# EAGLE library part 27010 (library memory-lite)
MEMORY

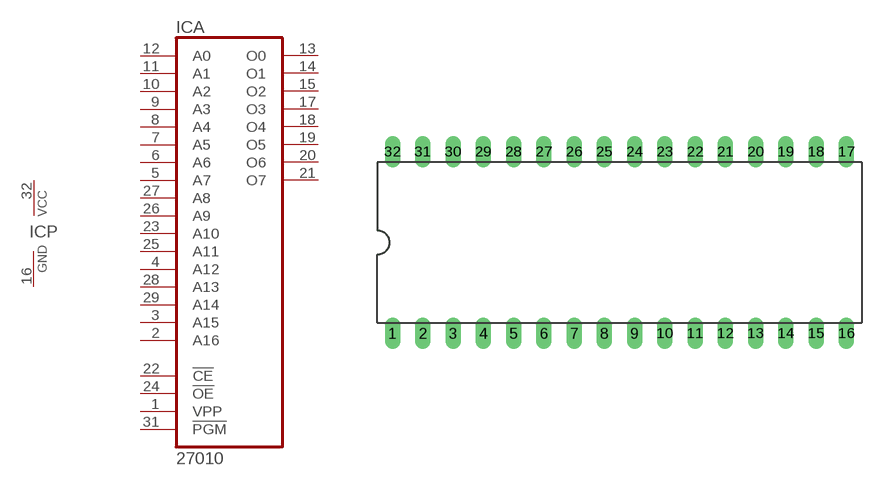
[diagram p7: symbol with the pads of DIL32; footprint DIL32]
Designator prefix IC; gates A=27010 P=PWRN

## 27010  [DIL32]
1  A:VPP  in
2  A:A16  in
3  A:A15  in
4  A:A12  in
5  A:A7  in
6  A:A6  in
7  A:A5  in
8  A:A4  in
9  A:A3  in
10  A:A2  in
11  A:A1  in
12  A:A0  in
13  A:O0  hiz
14  A:O1  hiz
15  A:O2  hiz
16  P:GND  pwr
17  A:O3  hiz
18  A:O4  hiz
19  A:O5  hiz
20  A:O6  hiz
21  A:O7  hiz
22  A:!CE  in
23  A:A10  in
24  A:!OE  in
25  A:A11  in
26  A:A9  in
27  A:A8  in
28  A:A13  in
29  A:A14  in
31  A:!PGM  in
32  P:VCC  pwr

## Footprint DIL32 (pad centres in mm)
Dual In Line Package
drill 0.813 long: 1 -19.05,-7.62; 2 -16.51,-7.62; 3 -13.97,-7.62; 4 -11.43,-7.62; 5 -8.89,-7.62; 6 -6.35,-7.62; 7 -3.81,-7.62; 8 -1.27,-7.62; 9 1.27,-7.62; 10 3.81,-7.62; 11 6.35,-7.62; 12 8.89,-7.62; 13 11.43,-7.62; 14 13.97,-7.62; 15 16.51,-7.62; 16 19.05,-7.62; 17 19.05,7.62; 18 16.51,7.62; 19 13.97,7.62; 20 11.43,7.62; 21 8.89,7.62; 22 6.35,7.62; 23 3.81,7.62; 24 1.27,7.62; 25 -1.27,7.62; 26 -3.81,7.62; 27 -6.35,7.62; 28 -8.89,7.62; 29 -11.43,7.62; 30 -13.97,7.62; 31 -16.51,7.62; 32 -19.05,7.62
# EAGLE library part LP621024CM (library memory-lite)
MEMORY

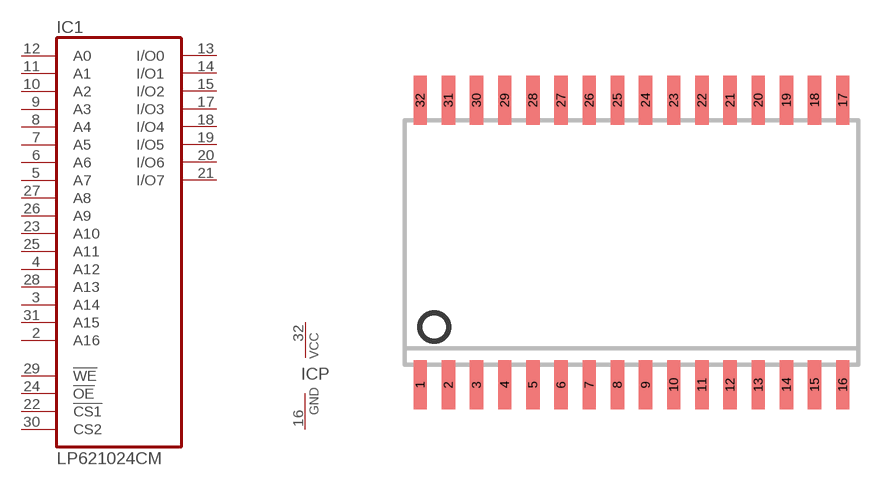
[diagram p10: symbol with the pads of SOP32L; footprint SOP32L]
Designator prefix IC; gates 1=621024 P=PWRN

## LP621024CM  [SOP32L]
1  1:NC  nc
2  1:A16  in
3  1:A14  in
4  1:A12  in
5  1:A7  in
6  1:A6  in
7  1:A5  in
8  1:A4  in
9  1:A3  in
10  1:A2  in
11  1:A1  in
12  1:A0  in
13  1:I/O0
14  1:I/O1
15  1:I/O2
16  P:GND  pwr
17  1:I/O3
18  1:I/O4
19  1:I/O5
20  1:I/O6
21  1:I/O7
22  1:!CS1  in
23  1:A10  in
24  1:!OE  in
25  1:A11  in
26  1:A9  in
27  1:A8  in
28  1:A13  in
29  1:!WE  in
30  1:CS2  in
31  1:A15  in
32  P:VCC  pwr

## Footprint SOP32L (pad centres in mm)
Small Outline Package large
smd 0.6 x 2.2: 1 -9.525,-6.416; 2 -8.255,-6.416; 3 -6.985,-6.416; 4 -5.715,-6.416; 5 -4.445,-6.416; 6 -3.175,-6.416; 7 -1.905,-6.416; 8 -0.635,-6.416; 9 0.635,-6.416; 10 1.905,-6.416; 11 3.175,-6.416; 12 4.445,-6.416; 13 5.715,-6.416; 14 6.985,-6.416; 15 8.255,-6.416; 16 9.525,-6.416; 17 9.525,6.416; 18 8.255,6.416; 19 6.985,6.416; 20 5.715,6.416; 21 4.445,6.416; 22 3.175,6.416; 23 1.905,6.416; 24 0.635,6.416; 25 -0.635,6.416; 26 -1.905,6.416; 27 -3.175,6.416; 28 -4.445,6.416; 29 -5.715,6.416; 30 -6.985,6.416; 31 -8.255,6.416; 32 -9.525,6.416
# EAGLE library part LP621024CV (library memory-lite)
MEMORY

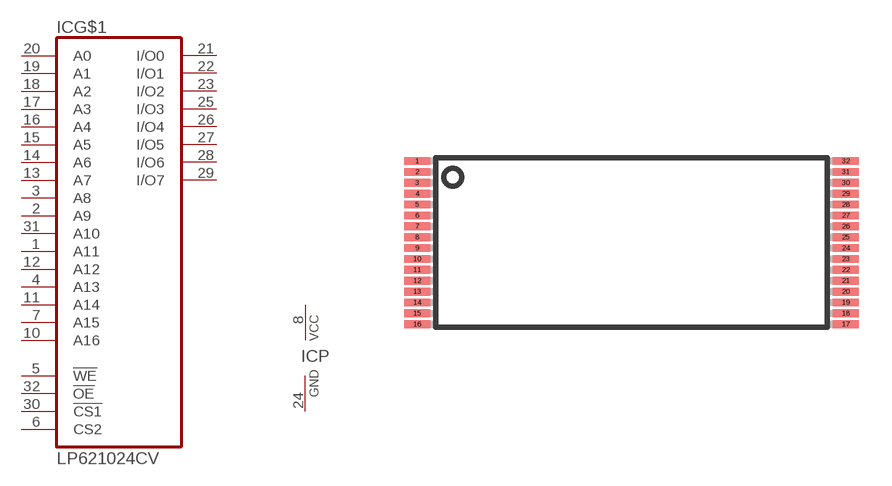
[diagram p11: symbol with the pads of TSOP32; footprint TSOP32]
Designator prefix IC; gates G$1=621024 P=PWRN

## LP621024CV  [TSOP32]
1  G$1:A11  in
2  G$1:A9  in
3  G$1:A8  in
4  G$1:A13  in
5  G$1:!WE  in
6  G$1:CS2  in
7  G$1:A15  in
8  P:VCC  pwr
9  G$1:NC  nc
10  G$1:A16  in
11  G$1:A14  in
12  G$1:A12  in
13  G$1:A7  in
14  G$1:A6  in
15  G$1:A5  in
16  G$1:A4  in
17  G$1:A3  in
18  G$1:A2  in
19  G$1:A1  in
20  G$1:A0  in
21  G$1:I/O0
22  G$1:I/O1
23  G$1:I/O2
24  P:GND  pwr
25  G$1:I/O3
26  G$1:I/O4
27  G$1:I/O5
28  G$1:I/O6
29  G$1:I/O7
30  G$1:!CS1  in
31  G$1:A10  in
32  G$1:!OE  in

## Footprint TSOP32 (pad centres in mm)
Thin Small Outline Package
smd 1.2 x 0.36: 1 -9.85,3.75; 2 -9.85,3.25; 3 -9.85,2.75; 4 -9.85,2.25; 5 -9.85,1.75; 6 -9.85,1.25; 7 -9.85,0.75; 8 -9.85,0.25; 9 -9.85,-0.25; 10 -9.85,-0.75; 11 -9.85,-1.25; 12 -9.85,-1.75; 13 -9.85,-2.25; 14 -9.85,-2.75; 15 -9.85,-3.25; 16 -9.85,-3.75; 17 9.85,-3.75; 18 9.85,-3.25; 19 9.85,-2.75; 20 9.85,-2.25; 21 9.85,-1.75; 22 9.85,-1.25; 23 9.85,-0.75; 24 9.85,-0.25; 25 9.85,0.25; 26 9.85,0.75; 27 9.85,1.25; 28 9.85,1.75; 29 9.85,2.25; 30 9.85,2.75; 31 9.85,3.25; 32 9.85,3.75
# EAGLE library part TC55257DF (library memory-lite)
MEMORY

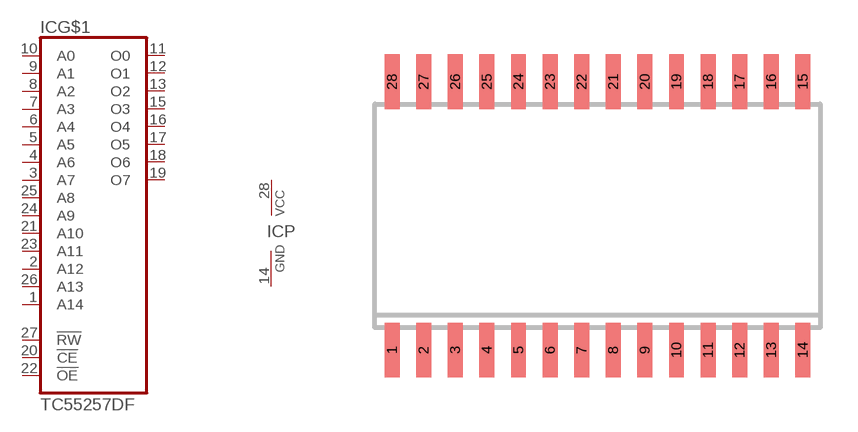
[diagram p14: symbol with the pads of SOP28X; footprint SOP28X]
Designator prefix IC; gates P=PWRN G$1=257

## TC55257DF  [SOP28X]
1  G$1:A14  in
2  G$1:A12  in
3  G$1:A7  in
4  G$1:A6  in
5  G$1:A5  in
6  G$1:A4  in
7  G$1:A3  in
8  G$1:A2  in
9  G$1:A1  in
10  G$1:A0  in
11  G$1:O0  hiz
12  G$1:O1  hiz
13  G$1:O2  hiz
14  P:GND  pwr
15  G$1:O3  hiz
16  G$1:O4  hiz
17  G$1:O5  hiz
18  G$1:O6  hiz
19  G$1:O7  hiz
20  G$1:!CE  in
21  G$1:A10  in
22  G$1:!OE  in
23  G$1:A11  in
24  G$1:A9  in
25  G$1:A8  in
26  G$1:A13  in
27  G$1:!RW  in
28  P:VCC  pwr

## Footprint SOP28X (pad centres in mm)
Small Outline Package X large
smd 0.6 x 2.2: 1 -8.255,-5.4; 2 -6.985,-5.4; 3 -5.715,-5.4; 4 -4.445,-5.4; 5 -3.175,-5.4; 6 -1.905,-5.4; 7 -0.635,-5.4; 8 0.635,-5.4; 9 1.905,-5.4; 10 3.175,-5.4; 11 4.445,-5.4; 12 5.715,-5.4; 13 6.985,-5.4; 14 8.255,-5.4; 15 8.255,5.4; 16 6.985,5.4; 17 5.715,5.4; 18 4.445,5.4; 19 3.175,5.4; 20 1.905,5.4; 21 0.635,5.4; 22 -0.635,5.4; 23 -1.905,5.4; 24 -3.175,5.4; 25 -4.445,5.4; 26 -5.715,5.4; 27 -6.985,5.4; 28 -8.255,5.4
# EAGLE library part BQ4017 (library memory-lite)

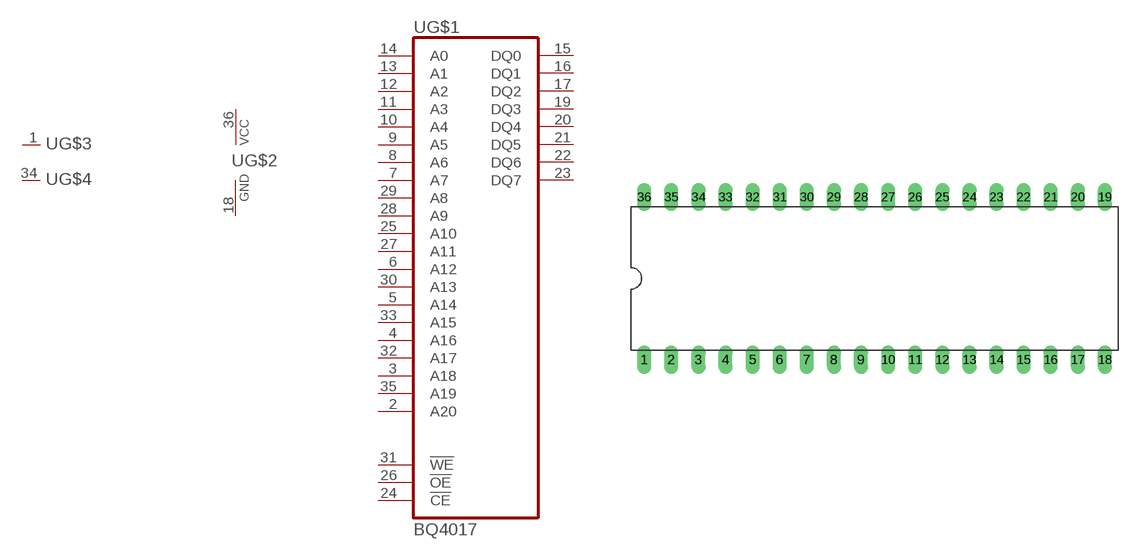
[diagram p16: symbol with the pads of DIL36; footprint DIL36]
Designator prefix -; gates G$1=BQ4017 G$2=PWRN G$3=NC G$4=NC

## BQ4017  [DIL36]
1  G$3:NC  nc
2  G$1:A20  in
3  G$1:A18  in
4  G$1:A16  in
5  G$1:A14  in
6  G$1:A12  in
7  G$1:A7  in
8  G$1:A6  in
9  G$1:A5  in
10  G$1:A4  in
11  G$1:A3  in
12  G$1:A2  in
13  G$1:A1  in
14  G$1:A0  in
15  G$1:DQ0
16  G$1:DQ1
17  G$1:DQ2
18  G$2:GND  pwr
19  G$1:DQ3
20  G$1:DQ4
21  G$1:DQ5
22  G$1:DQ6
23  G$1:DQ7
24  G$1:!CE  in
25  G$1:A10  in
26  G$1:!OE  in
27  G$1:A11  in
28  G$1:A9  in
29  G$1:A8  in
30  G$1:A13  in
31  G$1:!WE  in
32  G$1:A17  in
33  G$1:A15  in
34  G$4:NC  nc
35  G$1:A19  in
36  G$2:VCC  pwr

## Footprint DIL36 (pad centres in mm)
drill 0.813 long: 1 -21.59,-7.62; 2 -19.05,-7.62; 3 -16.51,-7.62; 4 -13.97,-7.62; 5 -11.43,-7.62; 6 -8.89,-7.62; 7 -6.35,-7.62; 8 -3.81,-7.62; 9 -1.27,-7.62; 10 1.27,-7.62; 11 3.81,-7.62; 12 6.35,-7.62; 13 8.89,-7.62; 14 11.43,-7.62; 15 13.97,-7.62; 16 16.51,-7.62; 17 19.05,-7.62; 18 21.59,-7.62; 19 21.59,7.62; 20 19.05,7.62; 21 16.51,7.62; 22 13.97,7.62; 23 11.43,7.62; 24 8.89,7.62; 25 6.35,7.62; 26 3.81,7.62; 27 1.27,7.62; 28 -1.27,7.62; 29 -3.81,7.62; 30 -6.35,7.62; 31 -8.89,7.62; 32 -11.43,7.62; 33 -13.97,7.62; 34 -16.51,7.62; 35 -19.05,7.62; 36 -21.59,7.62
